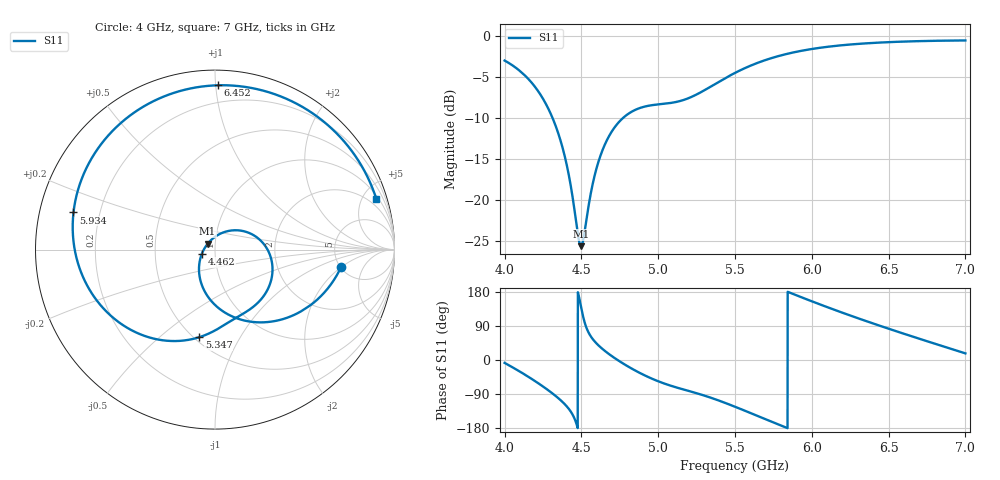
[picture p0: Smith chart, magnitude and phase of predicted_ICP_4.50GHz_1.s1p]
! ICP-predicted S11, target max centred GHz at -10 dB. Complex ensemble mean (passive and causal);
! its |S11| can differ slightly from the dB-domain mean reported in designs.csv.
!  Air_gap = 2.87mm
!  W_Patch = 17.89mm
!  L_Patch = 21.09mm
!  Sx = 1.09mm
!  Sy = 1.29mm
!  W_Patch1 = 15.47mm
!  WS = 1.22mm
!  Curve_Amp1 = 1.06mm
!  Extra = 1.58mm
# GHz S MA R 50
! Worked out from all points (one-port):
!   3001 points, 4 GHz to 7 GHz, reference 50 ohm
!   lowest |S11| = -25.6 dB at 4.497 GHz (marker M1), VSWR 1.11, Z = 46 + j2.98 ohm
!   |S11| at or under -10 dB: 4.312 GHz to 4.77 GHz (457.6 MHz wide, 10.1 % of centre)
!   S11 on the Smith chart (normalised r, x): 4 GHz: 5.13, -1.95; 4.462 GHz: 0.86, -0.04; 5.347 GHz: 0.53, -0.69; 5.934 GHz: 0.10, +0.13; 6.452 GHz: 0.09, +1.01; 7 GHz: 1.25, +6.27
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4  0.7102 -7.6
4.106  0.6055 -32.2
4.191  0.5003 -53.7
4.275  0.3762 -77.1
4.375  0.2124 -109.9
4.421  0.1372 -130.5
4.462  0.07778 -161.5
4.497  0.05224 141.7
4.513  0.05782 111.5
4.567  0.1172 58.9
4.613  0.1737 37.8
4.674  0.2397 17.3
4.75  0.3032 -3.8
4.835  0.3492 -24.4
4.937  0.3762 -45.3
5.125  0.3983 -73.2
5.347  0.4958 -100.2
5.5  0.5971 -123.3
5.668  0.6992 -151.1
5.775  0.7527 -168.9
5.875  0.7942 174.7
5.934  0.8151 165.3
6.081  0.8567 142.4
6.25  0.89 117.4
6.452  0.9155 89.1
6.625  0.9291 65.9
6.824  0.9384 40.0
7  0.9421 17.5
